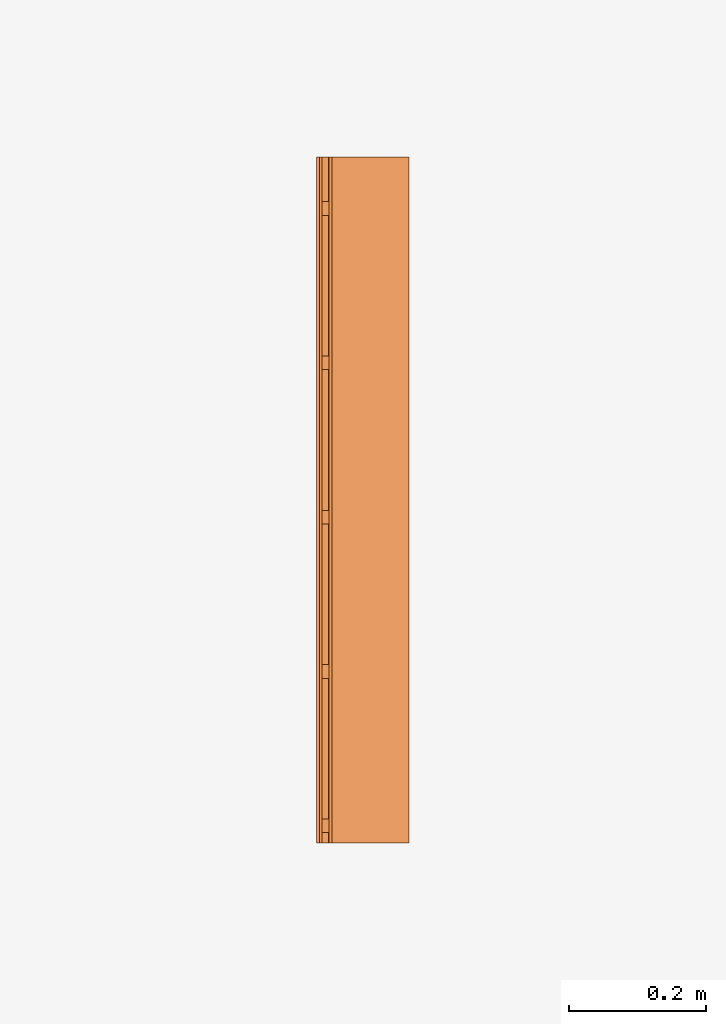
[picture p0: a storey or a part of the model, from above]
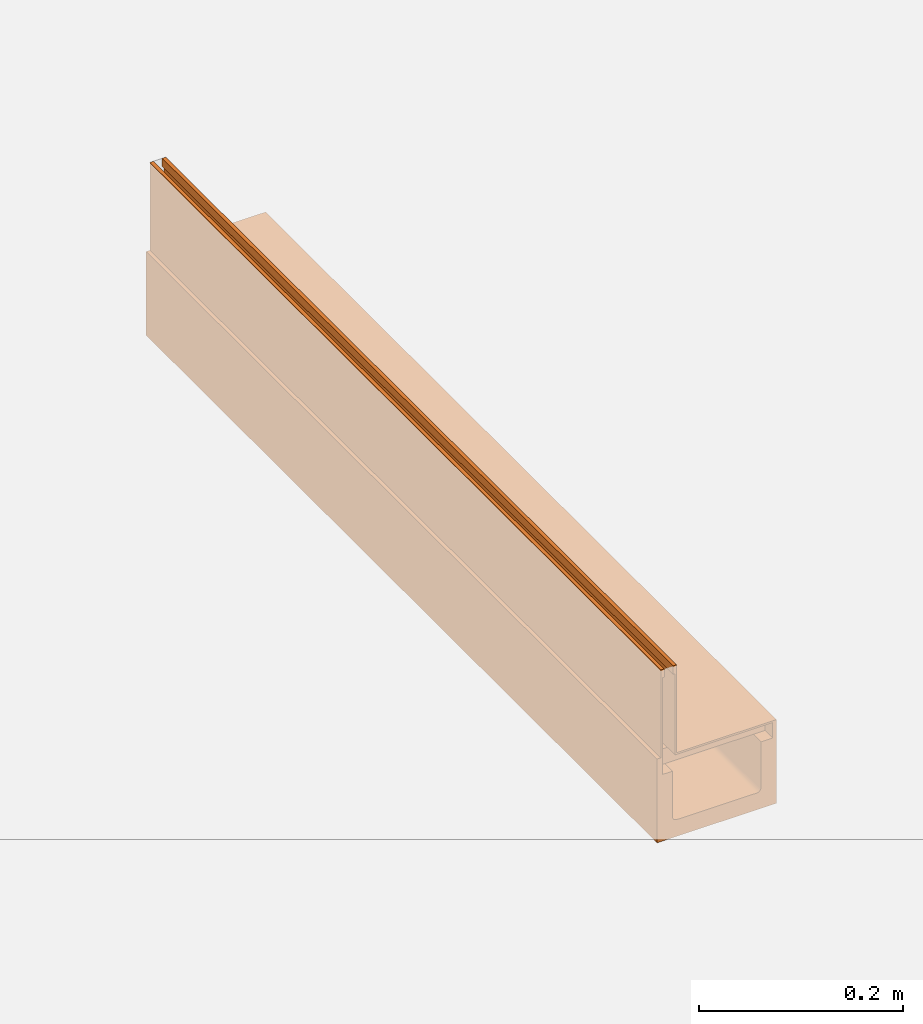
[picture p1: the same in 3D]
Properties of the parts of a building model (IFC2X3)

# File
Description: ViewDefinition [CoordinationView]
File name: 24000.ifc
Time: 2013-10-30T11:59:37
Written by: Autodesk Revit 2013
Made in: 20120221_2030(x64)

# IfcProject, Project Number
LongName: Project Name; Phase: Project Status

# IfcSite, Default
RefLatitude: 42, 21, 30, 344238; RefLongitude: -71, -3, -35, -194702; RefElevation: 0 mm

# IfcBuilding
Pset_BuildingCommon - NumberOfStoreys: 1
Other - Project Name: Project Name; Project Address: ## Street City, State Zip; Project Number: Project Number; Client Name: Owner; Project Issue Date: Issue Date; Project Status: Project Status

# IfcBuildingStorey, Level 1
LongName: Level 1; Elevation: 0 mm
Constraints - Elevation Base: 0; Elevation: 0 mm
Graphics - Symbol at End 1 Default: no; Symbol at End 2 Default: yes; Line Weight: 1; Color: 0; Symbol: M_Level Head - Circle: M_Level Head - Circle; Line Pattern: Center
Identity Data - Name: Level 1; Structural: no; Building Story: yes
Dimensions - Computation Height: 0 mm

# IfcBuildingElementProxy: 24000 - No 0.0 Constant Depth Channel - 1000mm LG - Invert Depth 130mm, Civil-Drainage-Channel-ACO-MultiDrain-M100DS-Brickslot-Channel-System:24000 - No 0.0 Constant Depth Channel - 1000mm LG - Invert Depth 130mm:24000 - No 0.0 Constant Depth Channel - 1000mm LG - Invert Depth 130mm:196059
In: Level 1
Material: Stainless Steel (F), Vienite® Synthetic Resin Concrete
Constraints - Moves With Nearby Elements: no; Level: Level: Level 1
Dimensions - Brickslot Void Length: 1000 mm; Custom_Void_length: 0 mm; Volume: 5775390 mm3; Brickslot Void Depth: 0 mm; Length: 1000 mm; EndCap Position: 1000 mm; Brickslot Access Unit Void Bottom Depth: -6605 mm; Brickslot Access Unit Void Depth: -6500 mm; FloorCut_Length: -1000 mm; FloorCut_Width: 135 mm; Floor Cut Gap: 105 mm; Depth: 150 mm; GratingLength: -1000 mm; EndCap_Height: 100 mm; ShallowOverallDepth: 100 mm; FloorCut_Depth: 100 mm; InvDepth: 80 mm; Length Drain: -1000 mm; ShallowInvDepth: 80 mm; Brickslot Access Unit Floor Cut Length: 500 mm
Phasing - Phase Created: New Construction
Construction - 23404_Universal Endcap (Male End): no; 23475_Load Class C250 & D400_Brickslot Grating_Stainless Steel_1000mm Long: yes; 23477_Load Class C250 & D400_Brickslot_Access Unit_Stainless Steel_500mm Long: no; 23404_Universal Endcap (Female End): no; 23476_Load Class C250 & D400_Brickslot Grating_Stainless Steel_500mm Long: no; Constant Depth Junction Channel: no; Shallow Depth Channel with seal: no; Constant Depth Channel: no; 23410_Sump Unit: no; Shallow Depth Channel: yes
Pset_BuildingElementProxyCommon - Reference: 24000 - No 0.0 Constant Depth Channel - 1000mm LG - Invert Depth 130mm
Data - Pre-formed Outlet Ø: N/A; Concrete Surround Volume - Load Class D 400 - Concrete Pavement: 0.17m³/m; Channel C.S.A: 0.009m²; Load Class: A 15 - D 400; Concrete Surround Volume - Load Class A 15 - Concrete Pavement: 0.07m³/m; Product Dimensions: 1000mm x 135mm x 150mm (LxWxH); Concrete Surround Volume - Load Class B 125 - C 250 - Concrete Pavement: 0.11m³/m; Product Standard: BS EN 1433:2002, CE marked; Product Weight: 14.9 Kg; Hydraulic Performance: http://www.aco.co.uk/download.php?id=173; Installation - Concrete Grade: Refer to brochure; ACO Hydraulic Design Software: http://www.acodesign.co.uk; Invert Depth: 130 mm
General - SerialNumber: 0; TagNumber: 0
Identity Data - e-mail Sales: customersupport@aco.co.uk; e-mail Technical: technical@aco.co.uk; Product Code: 24000; Type Comments: ACO MultiDrain M100DS 0.0 Constant Depth Channel 1000mm Long; Telephone: +44 (0)1462 816666; Fax: +44 (0)1462 815895; Assembly Code: D2040; Model Description: Channel drainage system; Maintenance guidelines: http://www.aco.co.uk/download.php?id=173; OmniClass Number: 23.70.50.24; Cost: 0; OmniClass Title: Rainwater Removal; Manufacturer: ACO Technologies plc - ACO Water Management Division; Address: ACO Business Park, Hitchin Road, Shefford, Bedfordshire, United Kingdom SG17 5TE; Watermark 1: This file is the property of ACO Technologies PLC; Watermarked With: BIM Manager Premium Suite; Installation guidelines: http://www.aco.co.uk/download.php?id=173; Price: POA - contact ACO; Product Page URL: http://www.aco.co.uk/product_detail.php?id=58; Model: ACO MultiDrain MDS Brickslot- M100DS; Product brochure: http://www.aco.co.uk/download.php?id=173; Watermarked By: www.aco.co.uk; Assembly Description: Rain Water Drainage; URL: www.aco.co.uk; Watermark 2: This file is water marked and users are prohibited to reproduce, adapt, distribute this information
Other - Created By: www.aco.co.uk; Revision: 1
Model Properties - Brickslot Grating Product code 23476: Load Class C250/D400 - Brickslot Stainless Steel - 500mm long x 105mm high -10mm Slot- Intake area - 1000mm²/m - 3.3 Kg; Brickslot Grating Product code 23475: Load Class C250/D400 - Brickslot Stainless Steel - 1000mm long x 105mm high -10mm Slot- Intake area - 1000mm²/m - 6.6 Kg; Brickslot Access Unit Product code 23477: Load Class C250/D400 - Brickslot Access Unit Stainless Steel - 500mm long x 105mm high -10mm Slot- Intake area - 1000mm²/m - 6.4 Kg; End Cap Product code 23404: No 306 Universl End Cap - 135mm wide x 300mm long - Spigot Ø110mm x 50mm long - Silver - Polypropylene - 0.16kg
Green Building Properties - Channel Recycled Material Content: 20% minimum; Edge Rail Recycled Material Content: Between 40% - 90%; Channel Recyclable: Fully recyclable; Edge Rail Recyclable: Fully recyclable
Materials and Finishes - Edge Rail Material: Stainless Steel Grade 304; Channel Colour: Brown; Channel Material: Vienite® Synthetic Resin Concrete; Edge Rail Colour: Self

# IfcOpeningElement: Recess (2)
In: Level 1
Constraints - Height Offset From Level: 0 mm; Room Bounding: yes; Level: Level: Level 1; Related to Mass: no
Phasing - Phase Created: New Construction
Dimensions - Thickness: 400 mm; Volume: 9984610000 mm3; Perimeter: 20000 mm; Area: 25000000 mm2
Structural - Structural: no; Enable Analytical Model: no
Graphics - Coarse Scale Fill Color: 0
Analytical Properties - Roughness: 1; Absorptance: 0.1; Thermal mass: 543920; Heat Transfer Coefficient (U): 2.0925; Thermal Resistance (R): 0.477897
Materials and Finishes - Structural Material: Earth
Construction - Function: 0; Default Thickness: 400 mm

# IfcSlab: Floor:Generic Floor - 400mm, Floor:Generic Floor - 400mm:193825
In: Level 1
PredefinedType: FLOOR; Material: Earth 400 mm
Constraints - Height Offset From Level: 0 mm; Room Bounding: yes; Level: Level: Level 1; Related to Mass: no
Phasing - Phase Created: New Construction
Dimensions - Thickness: 400 mm; Volume: 9984610000 mm3; Perimeter: 20000 mm; Area: 25000000 mm2
Structural - Structural: no; Enable Analytical Model: no
Pset_SlabCommon - Reference: Generic Floor - 400mm; IsExternal: no; LoadBearing: yes
Graphics - Coarse Scale Fill Color: 0
Analytical Properties - Roughness: 1; Absorptance: 0.1; Thermal mass: 543920; Heat Transfer Coefficient (U): 2.0925; Thermal Resistance (R): 0.477897
Materials and Finishes - Structural Material: Earth
Construction - Function: 0; Default Thickness: 400 mm
